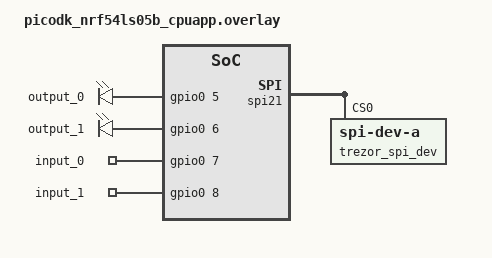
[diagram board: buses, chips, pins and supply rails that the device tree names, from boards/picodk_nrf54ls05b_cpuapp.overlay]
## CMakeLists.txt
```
#
# Copyright (c) 2018 Nordic Semiconductor
#
# SPDX-License-Identifier: LicenseRef-Nordic-5-Clause
#
cmake_minimum_required(VERSION 3.20.0)

find_package(Zephyr REQUIRED HINTS $ENV{ZEPHYR_BASE})
project(NONE)

add_compile_definitions(__BSD_VISIBLE=1)

# NORDIC SDK APP START
target_sources(app PRIVATE
        src/main.c
        src/ble/connection.c
        src/ble/advertising.c
        src/ble/ble_management.c
        src/ble/service.c
        src/ble/bonds.c
        src/ble/pairing.c
        src/ble/ble.c
        src/management/management.c
        src/prodtest/prodtest.c
        src/trz_comm/uart.c
        src/trz_comm/spi.c
        src/trz_comm/trz_comm.c
        src/signals/signals.c
        src/trezor-crypto/hmac.c
        src/trezor-crypto/sha2.c
        src/trezor-crypto/memzero.c
)

if(CONFIG_TRZ_CONSOLE OR CONFIG_TRZ_DEBUG_LINK)
  target_sources(app PRIVATE src/ble/aux_chan.c)
endif()
target_sources_ifdef(CONFIG_TRZ_CONSOLE app PRIVATE src/ble/console.c)
target_sources_ifdef(CONFIG_TRZ_DEBUG_LINK app PRIVATE src/ble/debug.c)

include_directories(src/signals/inc)
include_directories(src/trz_comm/inc)
include_directories(src/ble/inc)
include_directories(src/management/inc)
include_directories(src/prodtest/inc)
include_directories(src/trezor-crypto)

# NORDIC SDK APP END

zephyr_library_include_directories(.)
```

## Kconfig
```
#  * This file is part of the Trezor project, https://trezor.io/
#  *
#  * Copyright (c) SatoshiLabs
#  *
#  * This program is free software: you can redistribute it and/or modify
#  * it under the terms of the GNU General Public License as published by
#  * the Free Software Foundation, either version 3 of the License, or
#  * (at your option) any later version.
#  *
#  * This program is distributed in the hope that it will be useful,
#  * but WITHOUT ANY WARRANTY; without even the implied warranty of
#  * MERCHANTABILITY or FITNESS FOR A PARTICULAR PURPOSE.  See the
#  * GNU General Public License for more details.
#  *
#  * You should have received a copy of the GNU General Public License
#  * along with this program.  If not, see <http://www.gnu.org/licenses/>.

source "Kconfig.zephyr"

menu "Trezor BLE gateway configuration"

config DEFAULT_THREAD_STACK_SIZE
	int "Thread stack size"
	default 1024
	help
	  Common stack size used

config MODEL_IDENTIFIER
    int "Model identifier"

config TRZ_CONSOLE
	bool "BLE console service"
	depends on BT_PERIPHERAL
	select BT_GATT_DYNAMIC_DB
	help
	  Expose a second GATT service that carries an opaque byte console
	  between the STM32 and a bonded host: the prodtest CLI on
	  production-test firmware, debug logs on debug firmware. The bytes are
	  forwarded on their own inter-MCU service id (NRF_SERVICE_CONSOLE) and
	  are not interpreted by the nRF. The service is registered only while
	  the STM32 asks for it (the console flag of the advertising-on command,
	  set by prodtest and debug builds), so production STM32 firmware never
	  exposes it even from an image that carries this option. Leave it off
	  for models whose console stays on USB.

config TRZ_DEBUG_LINK
	bool "BLE debuglink service"
	depends on BT_PERIPHERAL
	select BT_GATT_DYNAMIC_DB
	help
	  Expose a GATT service that carries the debuglink between debug STM32
	  firmware and a bonded host, the counterpart of the USB debug
	  interface on models without USB. Forwarded on its own inter-MCU
	  service id (NRF_SERVICE_DEBUG). Registered only while the STM32 asks
	  for it (the debuglink flag of the advertising-on command, set by
	  --debug-link builds), so a shipping image can carry it; the STM32
	  firmware that enables it is the debug one, which answers debuglink
	  requests from any bonded host.

endmenu
```

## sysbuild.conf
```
# Sysbuild configuration file.

# Enable MCUboot
SB_CONFIG_BOOTLOADER_MCUBOOT=y
SB_CONFIG_MCUBOOT_MODE_SINGLE_APP=y
# Single-slot: app has no secondary slot, no OTA image management
SB_CONFIG_MCUBOOT_APP_SYNC_UPDATEABLE_IMAGES=n

# Use DTS fixed-partitions instead of pm_static.yml
SB_CONFIG_PARTITION_MANAGER=n

# Note: the ed25519 image-hash override (SB_CONFIG_BOOT_IMG_HASH_ALG_SHA512=n)
# lives in the board-scoped overlay sysbuild_nrf54l.conf, because that symbol
# only exists on the nRF54L series (NCS 3.3) and assigning it on nRF52832 /
# NCS 2.9 aborts the build with an "undefined symbol" Kconfig warning.
```

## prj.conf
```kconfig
#
# Copyright (c) 2018 Nordic Semiconductor
#
# SPDX-License-Identifier: LicenseRef-Nordic-5-Clause
#
CONFIG_NCS_APPLICATION_BOOT_BANNER_STRING="Trezor BLE Gateway"

CONFIG_CLOCK_CONTROL=y
CONFIG_CLOCK_CONTROL_NRF_K32SRC_RC=y
CONFIG_CLOCK_CONTROL_NRF_K32SRC_RC_CALIBRATION=y
CONFIG_CLOCK_CONTROL_NRF_K32SRC_500PPM=y
CONFIG_CLOCK_CONTROL_NRF_CALIBRATION_PERIOD=4000

CONFIG_MINIMAL_LIBC=y

# Enable the UART driver
CONFIG_UART_ASYNC_API=y
CONFIG_SERIAL=y

# Enable the SPI driver
CONFIG_SPI=y

CONFIG_GPIO=y

CONFIG_HEAP_MEM_POOL_SIZE=17000

# Enable system-wide Power Management
CONFIG_PM_DEVICE=y
CONFIG_PM_DEVICE_RUNTIME=y
CONFIG_POWEROFF=y

CONFIG_BT=y
CONFIG_BT_PERIPHERAL=y
CONFIG_BT_DEVICE_NAME="Trezor BLE"
CONFIG_BT_DEVICE_NAME_DYNAMIC=y
CONFIG_BT_DEVICE_APPEARANCE=128
CONFIG_BT_COMPANY_ID=0x0F29
CONFIG_BT_MAX_CONN=1
CONFIG_BT_MAX_PAIRED=8
CONFIG_BT_SMP=y
CONFIG_BT_SMP_ENFORCE_MITM=y
CONFIG_BT_SMP_SC_ONLY=y
CONFIG_BT_FILTER_ACCEPT_LIST=y
CONFIG_BT_BONDING_REQUIRED=y
CONFIG_BT_PRIVACY=y
CONFIG_BT_LL_SOFTDEVICE=y
CONFIG_BT_CTLR_TX_PWR_PLUS_4=y
CONFIG_BT_GAP_PERIPHERAL_PREF_PARAMS=y
CONFIG_BT_PERIPHERAL_PREF_MIN_INT=24
CONFIG_BT_PERIPHERAL_PREF_MAX_INT=36
CONFIG_BT_PERIPHERAL_PREF_TIMEOUT=400
CONFIG_BT_CTLR_PHY_2M=y
CONFIG_BT_USER_PHY_UPDATE=y
CONFIG_BT_BAS=y

CONFIG_BT_DIS=y
# Manufacturer/model are board/product-specific AND use different Kconfig symbol
# names across NCS versions (BT_DIS_MANUF/BT_DIS_MODEL on 2.9; the *_NAME_STR/
# *_NUMBER_STR symbols on 3.3). Set them per board in boards/<board>.conf.
CONFIG_BT_DIS_FW_REV=y
CONFIG_BT_DIS_FW_REV_STR="0.0.0.0"
CONFIG_BT_DIS_SW_REV=y
CONFIG_BT_DIS_SW_REV_STR="0.0.0.0"
CONFIG_BT_DIS_PNP=n
CONFIG_BT_DIS_SETTINGS=y
CONFIG_BT_DIS_STR_MAX=21

#PHY update needed for updating PHY request
CONFIG_BT_PHY_UPDATE=y
CONFIG_BT_USER_PHY_UPDATE=y
CONFIG_BT_CTLR_TX_PWR_DYNAMIC_CONTROL=y

# HCI ACL buffers size
CONFIG_BT_BUF_ACL_RX_SIZE=251

# L2CAP SDU/PDU TX MTU
CONFIG_BT_L2CAP_TX_MTU=247

# Enable bonding
CONFIG_BT_SETTINGS=y
CONFIG_FLASH=y
CONFIG_FLASH_PAGE_LAYOUT=y
CONFIG_FLASH_MAP=y
CONFIG_NVS=y
CONFIG_SETTINGS=y
CONFIG_SETTINGS_RUNTIME=y

# This example requires more stack
CONFIG_MAIN_STACK_SIZE=1152
CONFIG_SYSTEM_WORKQUEUE_STACK_SIZE=4096

CONFIG_POLL=y

# Config logger
CONFIG_LOG=n
CONFIG_UART_CONSOLE=n
CONFIG_LOG_BACKEND_UART=n

CONFIG_NANOPB=n

# bootloader
#CONFIG_SECURE_BOOT=y
```

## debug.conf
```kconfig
# Copyright (c) 2021 Nordic Semiconductor ASA
# SPDX-License-Identifier: Apache-2.0
#
# This is a Kconfig fragment which can be used to enable debug-related options
# in the application. See the README for more details.

# compiler
CONFIG_DEBUG_OPTIMIZATIONS=y

# logging
CONFIG_LOG=y
CONFIG_RTT_CONSOLE=y
CONFIG_USE_SEGGER_RTT=y
CONFIG_LOG_BACKEND_RTT=y

# enable console
CONFIG_CONSOLE=y

CONFIG_ASSERT=y

# Thread monitor and debug moninot exception to be able to debug BLE when running
# Applies only to application, not mcuboot.
# VTOR is currently at 0xC200 (mcuboot size + mcuboot_pad size)
CONFIG_THREAD_NAME=y
CONFIG_THREAD_MONITOR=y
CONFIG_CORTEX_M_DEBUG_MONITOR_HOOK=y
CONFIG_SEGGER_DEBUGMON=y
```

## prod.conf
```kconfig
# Copyright (c) 2021 Nordic Semiconductor ASA
# SPDX-License-Identifier: Apache-2.0
#
# This is a Kconfig fragment which can be used to enable debug-related options
# in the application. See the README for more details.

CONFIG_NRF_APPROTECT_LOCK=y

# Declared to the STM; pairs with mcuboot_prod.conf CONFIG_BOOT_PRODUCTION_KEY.
CONFIG_TREZOR_KEY_SET_PRODUCTION=y
```

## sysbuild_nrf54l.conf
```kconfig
# Board-scoped sysbuild overlay for the nRF54L series (NCS 3.3).
#
# The nRF54L series defaults the ed25519 image hash to SHA512; override it to
# SHA256. sysbuild's CMakeLists reads SB_CONFIG_BOOT_IMG_HASH_ALG_SHA512 and
# injects CONFIG_BOOT_IMG_HASH_ALG_SHA512=y into MCUboot, overriding
# sysbuild/mcuboot.conf. Setting it to n here lets CONFIG_BOOT_IMG_HASH_ALG_SHA256=y
# in mcuboot.conf win.
#
# This lives in a board-scoped overlay (not sysbuild.conf) because the symbol
# does not exist on nRF52832 / NCS 2.9 - assigning it there aborts the build
# with an "undefined symbol" Kconfig warning.
SB_CONFIG_BOOT_IMG_HASH_ALG_SHA512=n

# SB_CONFIG_MCUBOOT_HARDWARE_DOWNGRADE_PREVENTION is deliberately not set: NCS's
# provision_hex.cmake fails on a layout without NSIB slots (s0_partition), so
# build_sign_flash.sh generates the provision page with provision.py instead.
```

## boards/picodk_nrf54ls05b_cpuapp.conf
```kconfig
#
# Copyright (c) 2025 Trezor Company s.r.o.
#
# SPDX-License-Identifier: LicenseRef-Nordic-5-Clause
#
# Board-specific Kconfig for the picodk (nRF54LS05B), auto-merged by Zephyr for
# this board only.

# Device Information Service identity. NCS 3.3 (Zephyr 4.x) renamed the DIS
# manufacturer/model options; use the new symbol names here (the deprecated
# BT_DIS_MANUF/BT_DIS_MODEL would emit deprecation warnings on 3.3).
CONFIG_BT_DIS_MANUF_NAME_STR="Trezor Company s.r.o"
# TODO: set to the actual product/model name for this board.
CONFIG_BT_DIS_MODEL_NUMBER_STR="Trezor (picodk)"
```

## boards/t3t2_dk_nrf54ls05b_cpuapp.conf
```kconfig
#
# Copyright (c) 2025 Trezor Company s.r.o.
#
# SPDX-License-Identifier: LicenseRef-Nordic-5-Clause
#
# Board-specific Kconfig for the t3t2_dk (nRF54LS05B) board, auto-merged by
# Zephyr for this board only.

# Device Information Service identity. NCS 3.3 (Zephyr 4.x) renamed the DIS
# manufacturer/model options; use the new symbol names here (the deprecated
# BT_DIS_MANUF/BT_DIS_MODEL would emit deprecation warnings on 3.3).
CONFIG_BT_DIS_MANUF_NAME_STR="Trezor Company s.r.o."
# TODO: set to the actual product/model name for this board.
CONFIG_BT_DIS_MODEL_NUMBER_STR="Trezor T3T2"

# T3T2 has no USB, so the prodtest CLI and debug logs travel over the BLE
# console service, and the debuglink over its own service. The devkit is a
# development board; a shipping T3T2 image must not carry the debuglink.
CONFIG_TRZ_CONSOLE=y
CONFIG_TRZ_DEBUG_LINK=y
```

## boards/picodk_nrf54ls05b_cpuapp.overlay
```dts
/*
 * Copyright (c) 2025 Trezor Company s.r.o.
 *
 * SPDX-License-Identifier: LicenseRef-Nordic-5-Clause
 *
 * trezor-ble application devicetree glue for the picodk (nRF54LS05B) board.
 *
 * This maps the trezor-ble app's required devicetree contract onto the picodk
 * peripherals. The equivalent definitions for the t3w1 board live in its board
 * .dts (boards/arm/t3w1_revA_nrf52832/t3w1_revA_nrf52832.dts) and overlay.
 *
 * The app requires:
 *   - chosen  trezor,trz-uart          UART to the main Trezor SoC
 *   - alias   spi-master               SPIM controller
 *   - label   trezor_spi_dev           SPI device (CS sourced from controller)
 *   - aliases spi-ready / spi-request  SPI handshake GPIOs
 *   - aliases stay-in-bootloader / reserved-output  control GPIOs
 *
 * The UART/SPI instances reuse what the picodk board already enables (uart20,
 * spi21). The four handshake/control GPIOs below use PLACEHOLDER pins.
 *
 *  >>> TODO: set output_0/output_1/input_0/input_1 to the ACTUAL pins wired
 *  >>> between the picodk and the Trezor main SoC. Wrong pins build fine but
 *  >>> break SPI handshaking and bootloader entry at runtime.
 */

/ {
	chosen {
		/* Shares uart20 with the console, as t3w1 shares uart0. */
		trezor,trz-uart = &uart20;
	};

	outputs {
		compatible = "gpio-leds";
		output_0: output_0 {
			gpios = <&gpio0 5 GPIO_ACTIVE_HIGH>;   /* TODO: real pin (reserved-output) */
		};
		output_1: output_1 {
			gpios = <&gpio0 6 GPIO_ACTIVE_HIGH>;   /* TODO: real pin (spi-request) */
		};
	};

	inputs {
		compatible = "gpio-keys";
		input_0: input_0 {
			gpios = <&gpio0 7 (GPIO_PULL_DOWN | GPIO_ACTIVE_HIGH)>;  /* TODO: real pin (stay-in-bootloader) */
		};
		input_1: input_1 {
			gpios = <&gpio0 8 (GPIO_PULL_DOWN | GPIO_ACTIVE_HIGH)>;  /* TODO: real pin (spi-ready) */
		};
	};

	aliases {
		spi-master = &spi21;
		spi-ready = &input_1;
		spi-request = &output_1;
		stay-in-bootloader = &input_0;
		reserved-output = &output_0;
	};
};

/* Add the trezor_spi_dev label the app looks up via DT_NODELABEL(). The picodk
 * board already declares this node as reg_my_spi_master under &spi21; this adds
 * the second label the shared code expects. */
&spi21 {
	trezor_spi_dev: spi-dev-a@0 {
		reg = <0>;
	};
};
```

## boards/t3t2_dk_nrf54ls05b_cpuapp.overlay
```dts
/*
 * Copyright (c) 2025 Trezor Company s.r.o.
 *
 * SPDX-License-Identifier: LicenseRef-Nordic-5-Clause
 *
 * trezor-ble application devicetree glue for the t3t2_dk board.
 *
 * The UART link, SPI master (incl. trezor_spi_dev / CS) and the GPIO
 * handshake signals (spi-ready, spi-request, stay-in-bootloader,
 * reserved-output) are defined at board level in
 * boards/arm/t3t2_dk/, so they are shared with the MCUboot
 * image. This overlay only binds the app's logical contract to them, the
 * same way the t3w1 app overlay does.
 */

/ {
	chosen {
		/* Shares uart20 with the console, as t3w1 shares uart0. */
		trezor,trz-uart = &uart20;
	};

	aliases {
		spi-master = &spi21;
	};
};
```

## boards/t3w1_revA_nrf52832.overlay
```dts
/*
 * Copyright (c) 2022 Nordic Semiconductor ASA
 *
 * SPDX-License-Identifier: LicenseRef-Nordic-5-Clause
 */
/ {
	chosen {
		trezor,trz-uart = &uart0;
	};

	aliases {
		spi-master = &spi0;
	};
};
```

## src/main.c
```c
/*
 * This file is part of the Trezor project, https://trezor.io/
 *
 * Copyright (c) SatoshiLabs
 *
 * This program is free software: you can redistribute it and/or modify
 * it under the terms of the GNU General Public License as published by
 * the Free Software Foundation, either version 3 of the License, or
 * (at your option) any later version.
 *
 * This program is distributed in the hope that it will be useful,
 * but WITHOUT ANY WARRANTY; without even the implied warranty of
 * MERCHANTABILITY or FITNESS FOR A PARTICULAR PURPOSE.  See the
 * GNU General Public License for more details.
 *
 * You should have received a copy of the GNU General Public License
 * along with this program.  If not, see <http://www.gnu.org/licenses/>.
 */

#include <zephyr/drivers/gpio.h>
#include <zephyr/drivers/uart.h>
#include <zephyr/kernel.h>
#include <zephyr/types.h>

#include <soc.h>
#include <zephyr/device.h>
#include <zephyr/devicetree.h>

#include <zephyr/bluetooth/bluetooth.h>
#include <zephyr/bluetooth/conn.h>
#include <zephyr/bluetooth/gatt.h>
#include <zephyr/bluetooth/hci.h>
#include <zephyr/bluetooth/uuid.h>

#include <zephyr/settings/settings.h>

#include <zephyr/logging/log.h>

#include <ble/ble.h>
#include <management/management.h>
#include <prodtest/prodtest.h>
#include <signals/signals.h>
#include <trz_comm/trz_comm.h>

#define LOG_MODULE_NAME main
LOG_MODULE_REGISTER(LOG_MODULE_NAME);

int main(void) {
  LOG_INF("Initializing");

  signals_init();

  trz_comm_init();

  ble_init();

  management_init();

  prodtest_init();

  for (;;) {
    k_sleep(K_FOREVER);
  }
}
```
